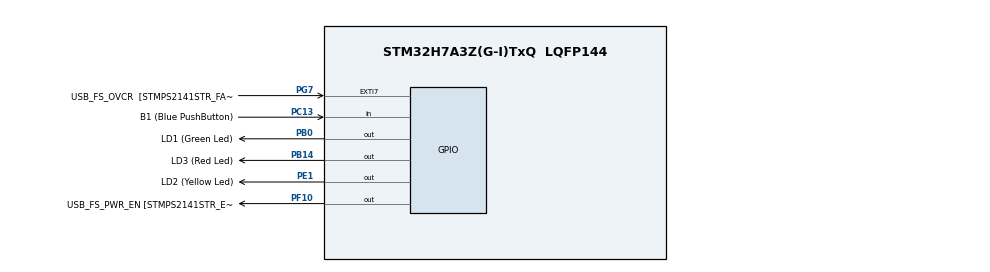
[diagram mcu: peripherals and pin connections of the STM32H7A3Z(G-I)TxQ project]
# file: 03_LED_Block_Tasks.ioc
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Mcu.Family=STM32H7
Mcu.Name=STM32H7A3Z(G-I)TxQ
Mcu.Package=LQFP144
NVIC.PriorityGroup=NVIC_PRIORITYGROUP_4
NVIC.TIM6_DAC_IRQn=true\:15\:0\:false\:false\:true\:false\:true\:true
NVIC.TimeBase=TIM6_DAC_IRQn
NVIC.TimeBaseIP=TIM6
PA10.GPIO_Label=USB_FS_ID [ZX62RD-AB-5P8_ID]
PA10.Signal=USB_OTG_HS_ID
PA11.GPIO_Label=USB_FS_N [USBLC6-2SC6_IO_1]
PA11.Signal=USB_OTG_HS_DM
PA12.GPIO_Label=USB_FS_P [USBLC6-2SC6_IO_2]
PA12.Signal=USB_OTG_HS_DP
PA9.GPIO_Label=USB_FS_VBUS  [ZX62RD-AB-5P8_VBUS]
PA9.Signal=USB_OTG_HS_VBUS
PB0.GPIO_Label=LD1 (Green Led)
PB0.GPIO_Speed=GPIO_SPEED_FREQ_VERY_HIGH
PB0.Signal=GPIO_Output
PB14.GPIO_Label=LD3 (Red Led)
PB14.GPIO_Speed=GPIO_SPEED_FREQ_VERY_HIGH
PB14.Signal=GPIO_Output
PC13.GPIO_Label=B1 (Blue PushButton)
PC13.Signal=GPIO_Input
PC14-OSC32_IN.GPIO_Label=OSC32_IN
PC14-OSC32_IN.Signal=RCC_OSC32_IN
PC15-OSC32_OUT.GPIO_Label=OSC32_OUT
PC15-OSC32_OUT.Signal=RCC_OSC32_OUT
PD8.GPIO_Label=STLINK_RX
PD8.Signal=USART3_TX
PD9.GPIO_Label=STLINK_TX
PD9.Signal=USART3_RX
PE1.GPIO_Label=LD2 (Yellow Led)
PE1.GPIO_Speed=GPIO_SPEED_FREQ_VERY_HIGH
PE1.Signal=GPIO_Output
PF10.GPIO_Label=USB_FS_PWR_EN [STMPS2141STR_EN]
PF10.GPIO_Speed=GPIO_SPEED_FREQ_LOW
PF10.Signal=GPIO_Output
PG7.GPIO_Label=USB_FS_OVCR  [STMPS2141STR_FAULT]
PG7.Signal=GPXTI7
PH0-OSC_IN.GPIO_Label=PH0-MCU
PH0-OSC_IN.Signal=RCC_OSC_IN
PH1-OSC_OUT.GPIO_Label=PH1-MCU
PH1-OSC_OUT.Signal=RCC_OSC_OUT
ProjectManager.HeapSize=0x200
ProjectManager.StackSize=0x400
ProjectManager.TargetToolchain=STM32CubeIDE
RCC.ADCFreq_Value=129000000
RCC.APB1Freq_Value=140000000
RCC.APB2Freq_Value=140000000
RCC.APB3Freq_Value=140000000
RCC.APB4Freq_Value=140000000
RCC.CDPPRE=RCC_APB3_DIV2
RCC.CDPPRE1=RCC_APB1_DIV2
RCC.CDPPRE2=RCC_APB2_DIV2
RCC.CortexFreq_Value=280000000
RCC.DIVM1=4
RCC.DIVM3=1
RCC.DIVN1=35
RCC.DIVN3=24
RCC.DIVQ1=4
RCC.HCLKFreq_Value=280000000
RCC.HSE_VALUE=8000000
RCC.PLLFRACN=0
RCC.PWR_Regulator_Voltage_Scale=PWR_REGULATOR_VOLTAGE_SCALE0
RCC.SRDPPRE=RCC_APB4_DIV2
RCC.SYSCLKFreq_VALUE=280000000
RCC.SYSCLKSource=RCC_SYSCLKSOURCE_PLLCLK
RCC.SupplySource=PWR_DIRECT_SMPS_SUPPLY
RCC.USBCLockSelection=RCC_USBCLKSOURCE_HSI48
RCC.USBFreq_Value=48000000
VP_SYS_VS_tim6.Mode=TIM6
board=NUCLEO-H7A3ZI-Q

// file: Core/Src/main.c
/* USER CODE BEGIN Header */
/**
  ******************************************************************************
  * @file           : main.c
  * @brief          : Main program body
  ******************************************************************************
  * @attention
  *
  * Copyright (c) 2023 STMicroelectronics.
  * All rights reserved.
  *
  * This software is licensed under terms that can be found in the LICENSE file
  * in the root directory of this software component.
  * If no LICENSE file comes with this software, it is provided AS-IS.
  *
  ******************************************************************************
  */
/* USER CODE END Header */
#include "main.h"

void SystemClock_Config(void);
static void MX_GPIO_Init(void);

int main(void)
{

  /* MCU Configuration--------------------------------------------------------*/

  /* Reset of all peripherals, Initializes the Flash interface and the Systick. */
  HAL_Init();

  /* Configure the system clock */
  SystemClock_Config();

  /* Initialize all configured peripherals */
  MX_GPIO_Init();

  /* Infinite loop */
  while (1)
  {

  }
}

void SystemClock_Config(void)
{
  RCC_OscInitTypeDef RCC_OscInitStruct = {0};
  RCC_ClkInitTypeDef RCC_ClkInitStruct = {0};

  /*AXI clock gating */
  RCC->CKGAENR = 0xFFFFFFFF;

  /** Supply configuration update enable
  */
  HAL_PWREx_ConfigSupply(PWR_DIRECT_SMPS_SUPPLY);

  /** Configure the main internal regulator output voltage
  */
  __HAL_PWR_VOLTAGESCALING_CONFIG(PWR_REGULATOR_VOLTAGE_SCALE0);

  while(!__HAL_PWR_GET_FLAG(PWR_FLAG_VOSRDY)) {}

  /** Initializes the RCC Oscillators according to the specified parameters
  * in the RCC_OscInitTypeDef structure.
  */
  RCC_OscInitStruct.OscillatorType = RCC_OSCILLATORTYPE_HSI;
  RCC_OscInitStruct.HSIState = RCC_HSI_DIV1;
  RCC_OscInitStruct.HSICalibrationValue = 64;
  RCC_OscInitStruct.PLL.PLLState = RCC_PLL_ON;
  RCC_OscInitStruct.PLL.PLLSource = RCC_PLLSOURCE_HSI;
  RCC_OscInitStruct.PLL.PLLM = 4;
  RCC_OscInitStruct.PLL.PLLN = 8;
  RCC_OscInitStruct.PLL.PLLP = 2;
  RCC_OscInitStruct.PLL.PLLQ = 4;
  RCC_OscInitStruct.PLL.PLLR = 2;
  RCC_OscInitStruct.PLL.PLLRGE = RCC_PLL1VCIRANGE_3;
  RCC_OscInitStruct.PLL.PLLVCOSEL = RCC_PLL1VCOWIDE;
  RCC_OscInitStruct.PLL.PLLFRACN = 0;
  if (HAL_RCC_OscConfig(&RCC_OscInitStruct) != HAL_OK)
  {
    Error_Handler();
  }

  /** Initializes the CPU, AHB and APB buses clocks
  */
  RCC_ClkInitStruct.ClockType = RCC_CLOCKTYPE_HCLK|RCC_CLOCKTYPE_SYSCLK
                              |RCC_CLOCKTYPE_PCLK1|RCC_CLOCKTYPE_PCLK2
                              |RCC_CLOCKTYPE_D3PCLK1|RCC_CLOCKTYPE_D1PCLK1;
  RCC_ClkInitStruct.SYSCLKSource = RCC_SYSCLKSOURCE_PLLCLK;
  RCC_ClkInitStruct.SYSCLKDivider = RCC_SYSCLK_DIV1;
  RCC_ClkInitStruct.AHBCLKDivider = RCC_HCLK_DIV1;
  RCC_ClkInitStruct.APB3CLKDivider = RCC_APB3_DIV1;
  RCC_ClkInitStruct.APB1CLKDivider = RCC_APB1_DIV1;
  RCC_ClkInitStruct.APB2CLKDivider = RCC_APB2_DIV1;
  RCC_ClkInitStruct.APB4CLKDivider = RCC_APB4_DIV1;

  if (HAL_RCC_ClockConfig(&RCC_ClkInitStruct, FLASH_LATENCY_1) != HAL_OK)
  {
    Error_Handler();
  }
}

static void MX_GPIO_Init(void)
{
  GPIO_InitTypeDef GPIO_InitStruct = {0};

  /* GPIO Ports Clock Enable */
  __HAL_RCC_GPIOC_CLK_ENABLE();
  __HAL_RCC_GPIOF_CLK_ENABLE();
  __HAL_RCC_GPIOH_CLK_ENABLE();
  __HAL_RCC_GPIOB_CLK_ENABLE();
  __HAL_RCC_GPIOD_CLK_ENABLE();
  __HAL_RCC_GPIOG_CLK_ENABLE();
  __HAL_RCC_GPIOA_CLK_ENABLE();
  __HAL_RCC_GPIOE_CLK_ENABLE();

  /*Configure GPIO pin Output Level */
  HAL_GPIO_WritePin(USB_FS_PWR_EN_GPIO_Port, USB_FS_PWR_EN_Pin, GPIO_PIN_RESET);

  /*Configure GPIO pin Output Level */
  HAL_GPIO_WritePin(GPIOB, LD1_Pin|LD3_Pin, GPIO_PIN_RESET);

  /*Configure GPIO pin Output Level */
  HAL_GPIO_WritePin(LD2_GPIO_Port, LD2_Pin, GPIO_PIN_RESET);

  /*Configure GPIO pin : B1_Pin */
  GPIO_InitStruct.Pin = B1_Pin;
  GPIO_InitStruct.Mode = GPIO_MODE_INPUT;
  GPIO_InitStruct.Pull = GPIO_NOPULL;
  HAL_GPIO_Init(B1_GPIO_Port, &GPIO_InitStruct);

  /*Configure GPIO pin : USB_FS_PWR_EN_Pin */
  GPIO_InitStruct.Pin = USB_FS_PWR_EN_Pin;
  GPIO_InitStruct.Mode = GPIO_MODE_OUTPUT_PP;
  GPIO_InitStruct.Pull = GPIO_NOPULL;
  GPIO_InitStruct.Speed = GPIO_SPEED_FREQ_LOW;
  HAL_GPIO_Init(USB_FS_PWR_EN_GPIO_Port, &GPIO_InitStruct);

  /*Configure GPIO pins : LD1_Pin LD3_Pin */
  GPIO_InitStruct.Pin = LD1_Pin|LD3_Pin;
  GPIO_InitStruct.Mode = GPIO_MODE_OUTPUT_PP;
  GPIO_InitStruct.Pull = GPIO_NOPULL;
  GPIO_InitStruct.Speed = GPIO_SPEED_FREQ_LOW;
  HAL_GPIO_Init(GPIOB, &GPIO_InitStruct);

  /*Configure GPIO pins : STLINK_RX_Pin STLINK_TX_Pin */
  GPIO_InitStruct.Pin = STLINK_RX_Pin|STLINK_TX_Pin;
  GPIO_InitStruct.Mode = GPIO_MODE_AF_PP;
  GPIO_InitStruct.Pull = GPIO_NOPULL;
  GPIO_InitStruct.Speed = GPIO_SPEED_FREQ_LOW;
  GPIO_InitStruct.Alternate = GPIO_AF7_USART3;
  HAL_GPIO_Init(GPIOD, &GPIO_InitStruct);

  /*Configure GPIO pin : USB_FS_OVCR_Pin */
  GPIO_InitStruct.Pin = USB_FS_OVCR_Pin;
  GPIO_InitStruct.Mode = GPIO_MODE_IT_RISING;
  GPIO_InitStruct.Pull = GPIO_NOPULL;
  HAL_GPIO_Init(USB_FS_OVCR_GPIO_Port, &GPIO_InitStruct);

  /*Configure GPIO pin : USB_FS_ID_Pin */
  GPIO_InitStruct.Pin = USB_FS_ID_Pin;
  GPIO_InitStruct.Mode = GPIO_MODE_AF_PP;
  GPIO_InitStruct.Pull = GPIO_NOPULL;
  GPIO_InitStruct.Speed = GPIO_SPEED_FREQ_LOW;
  GPIO_InitStruct.Alternate = GPIO_AF10_OTG1_HS;
  HAL_GPIO_Init(USB_FS_ID_GPIO_Port, &GPIO_InitStruct);

  /*Configure GPIO pins : USB_FS_N_Pin USB_FS_P_Pin */
  GPIO_InitStruct.Pin = USB_FS_N_Pin|USB_FS_P_Pin;
  GPIO_InitStruct.Mode = GPIO_MODE_AF_PP;
  GPIO_InitStruct.Pull = GPIO_NOPULL;
  GPIO_InitStruct.Speed = GPIO_SPEED_FREQ_LOW;
  HAL_GPIO_Init(GPIOA, &GPIO_InitStruct);

  /*Configure GPIO pin : LD2_Pin */
  GPIO_InitStruct.Pin = LD2_Pin;
  GPIO_InitStruct.Mode = GPIO_MODE_OUTPUT_PP;
  GPIO_InitStruct.Pull = GPIO_NOPULL;
  GPIO_InitStruct.Speed = GPIO_SPEED_FREQ_LOW;
  HAL_GPIO_Init(LD2_GPIO_Port, &GPIO_InitStruct);

}

void HAL_TIM_PeriodElapsedCallback(TIM_HandleTypeDef *htim)
{
  if (htim->Instance == TIM6) {
    HAL_IncTick();
  }
}

void Error_Handler(void)
{
  __disable_irq();
  while (1)
  {
  }
}
